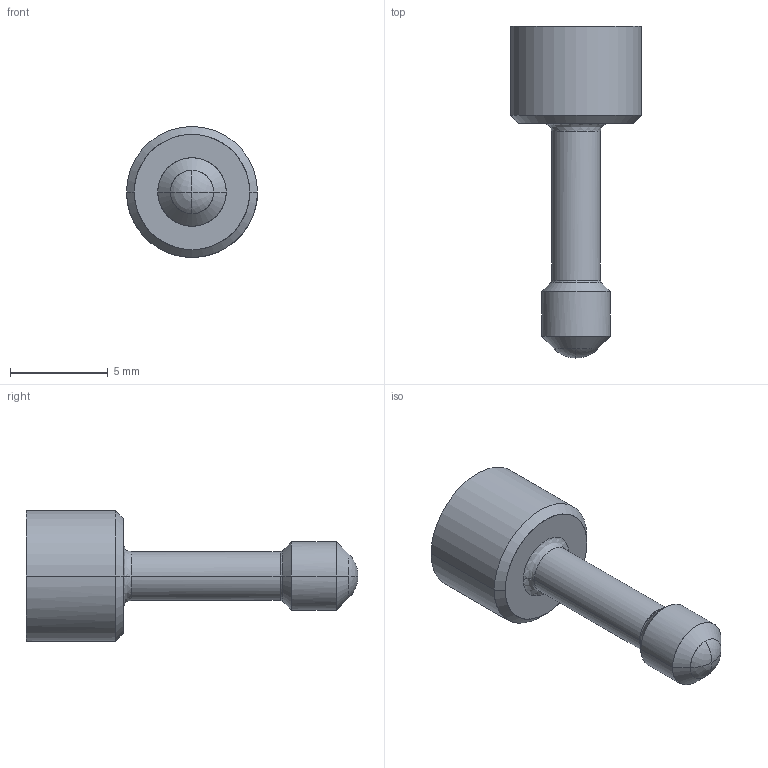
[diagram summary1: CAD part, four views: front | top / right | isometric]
IGES file: header records copied from the file, then geometry measured from it (millimetres).
Start section: START RECORD GO HERE.
Global section: file name: ia671720.igs; native system: DASSAULT SYSTEMES CATIA V5 R20 - www.3ds.com; preprocessor: CATIA Version 5 Release 20 ; author: Utente; organization: NB04-ASUS; date: 20201108.074310; units: millimetre
Bounding box: 6.7 x 16.97 x 6.7 mm (x, y, z)
Surface area: 281.4 mm2 (no closed solid volume)
Topology: 0 solids, 0 shells, 59 faces, 283 edges, 282 vertices
Faces by surface type: revolution 38, plane 21
